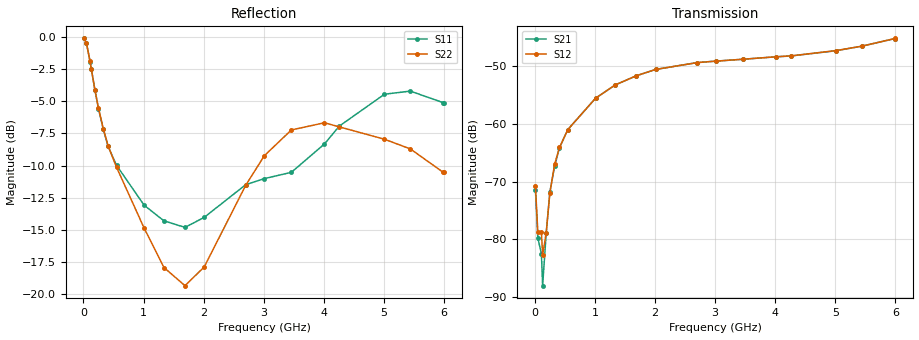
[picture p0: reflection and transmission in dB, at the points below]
!Agilent Technologies,N5230A,MY45001650,A.07.50.48
!Agilent N5230A: A.07.50.48
!Date: Saturday, July 08, 2017 15:42:33
!Correction: S11(Full 2 Port(1,2))
!S21(Full 2 Port(1,2))
!S12(Full 2 Port(1,2))
!S22(Full 2 Port(1,2))
!S2P File: Measurements: S11, S21, S12, S22:
# Hz S  dB  R 50
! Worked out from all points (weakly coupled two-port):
!   600 points, 10 MHz to 6 GHz, reference 50 ohm
!   highest |S21| = -45.18 dB at 5.99 GHz (marker M1); lowest = -88.0 dB at 130 MHz (marker M2)
!   lowest |S11| = -14.8 dB at 1.69 GHz (marker M3), VSWR 1.44, Z = 34.6 + j1.18 ohm
!   |S11| at or under -10 dB: 553.9 MHz to 3.664 GHz (3.11 GHz wide, 147 % of centre)
!   |S22| runs from -19.5 to -0.1 dB; largest |S21 - S12| = 0.00052
!   S11 on the Smith chart (normalised r, x): 10 MHz: 3, -20; 110 MHz: 0.52, -1.89; 330 MHz: 0.55, -0.56; 2.7 GHz: 0.59, +0.08; 4.26 GHz: 1.38, +1.12; 6 GHz: 2.61, -1.43
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1e7  -0.11 -5.7  -71.34 -19.5  -70.71 115.4  -0.12 -5.7
5e7  -0.49 -26.6  -79.72 34.1  -78.70 41.7  -0.50 -26.6
1.1e8  -1.91 -53.1  -82.52 45.1  -78.78 36.6  -1.90 -53.0
1.3e8  -2.47 -60.2  -88.02 121.0  -82.73 40.6  -2.46 -60.2
1.9e8  -4.12 -78.8  -78.87 116.9  -78.82 116.4  -4.09 -78.9
2.5e8  -5.58 -92.8  -71.79 107.1  -72.00 106.5  -5.53 -93.0
3.3e8  -7.18 -109.0  -67.28 92.5  -66.94 91.4  -7.13 -108.2
4.1e8  -8.51 -121.8  -64.11 79.9  -64.05 79.0  -8.46 -120.5
5.5e8  -9.97 -140.0  -60.94 61.5  -60.94 61.7  -10.12 -137.6
1.01e9  -13.08 -172.4  -55.52 13.7  -55.52 13.8  -14.86 -167.6
1.34e9  -14.29 175.1  -53.20 -17.5  -53.19 -17.5  -17.92 -179.5
1.69e9  -14.80 174.8  -51.62 -50.5  -51.61 -50.4  -19.33 -176.2
2.01e9  -14.02 176.9  -50.52 -80.7  -50.52 -80.7  -17.87 -174.5
2.7e9  -11.48 165.4  -49.33 -146.9  -49.34 -147.1  -11.53 161.5
3.01e9  -11.01 149.5  -49.08 -176.5  -49.08 -176.1  -9.23 148.3
3.46e9  -10.52 117.1  -48.76 139.4  -48.75 139.4  -7.23 132.1
4.01e9  -8.32 64.0  -48.33 86.3  -48.33 86.3  -6.67 109.5
4.26e9  -6.92 45.9  -48.19 63.5  -48.17 63.6  -6.99 97.9
5.01e9  -4.45 12.4  -47.28 0.8  -47.25 0.7  -7.95 53.0
5.44e9  -4.21 0.1  -46.49 -33.3  -46.49 -33.3  -8.70 23.9
5.99e9  -5.11 -19.4  -45.18 -74.9  -45.16 -74.8  -10.53 -8.8
6e9  -5.13 -20.0  -45.20 -75.8  -45.13 -75.7  -10.52 -9.4
